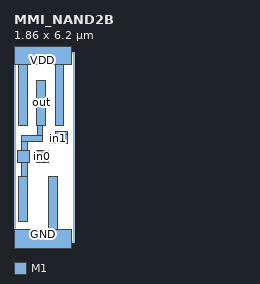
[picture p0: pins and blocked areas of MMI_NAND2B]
MACRO MMI_NAND2B
	CLASS CORE ;
	FOREIGN MMI_NAND2B 0 0 ;
	SIZE 1.86 BY 6.2 ;
	SYMMETRY X Y ;
	SITE CORE1 ;
	PIN out
		DIRECTION output ;
		USE SIGNAL ;
		PORT
			LAYER M1 ;
			RECT 0.75 3.805 1.03 5.275 ;
			LAYER M1 ;
			RECT 0.755 3.465 0.945 3.805 ;
			LAYER M1 ;
			RECT 0.245 3.27 0.945 3.465 ;
			LAYER M1 ;
			RECT 0.245 2.98 0.435 3.27 ;
			LAYER M1 ;
			RECT 0.12 2.6 0.5 2.98 ;
			LAYER M1 ;
			RECT 0.245 2.125 0.435 2.6 ;
			LAYER M1 ;
			RECT 0.16 0.655 0.44 2.125 ;
		END
		AntennaDiffArea 1.2859 ;
	END out
	PIN in1
		DIRECTION input ;
		USE SIGNAL ;
		PORT
			LAYER M1 ;
			RECT 1.36 3.51 1.74 3.6 ;
			LAYER M1 ;
			RECT 1.15 3.23 1.74 3.51 ;
			LAYER M1 ;
			RECT 1.36 3.22 1.74 3.23 ;
		END
		AntennaGateArea 0.462 ;
	END in1
	PIN GND
		DIRECTION inout ;
		USE GROUND ;
		PORT
			LAYER M1 ;
			RECT 1.13 0.42 1.41 2.125 ;
			LAYER M1 ;
			RECT 0 -0.42 1.86 0.42 ;
		END
	END GND
	PIN VDD
		DIRECTION inout ;
		USE POWER ;
		PORT
			LAYER M1 ;
			RECT 0 5.78 1.86 6.62 ;
			LAYER M1 ;
			RECT 0.16 3.805 0.44 5.78 ;
			LAYER M1 ;
			RECT 1.34 3.805 1.62 5.78 ;
		END
	END VDD
	PIN in0
		DIRECTION input ;
		USE SIGNAL ;
		PORT
			LAYER M1 ;
			RECT 0.74 2.93 1.12 2.98 ;
			LAYER M1 ;
			RECT 0.7 2.65 1.12 2.93 ;
			LAYER M1 ;
			RECT 0.74 2.6 1.12 2.65 ;
		END
		AntennaGateArea 0.462 ;
	END in0
	OBS
	END
END MMI_NAND2B
